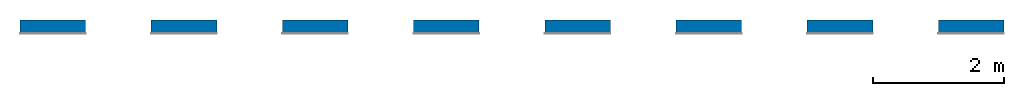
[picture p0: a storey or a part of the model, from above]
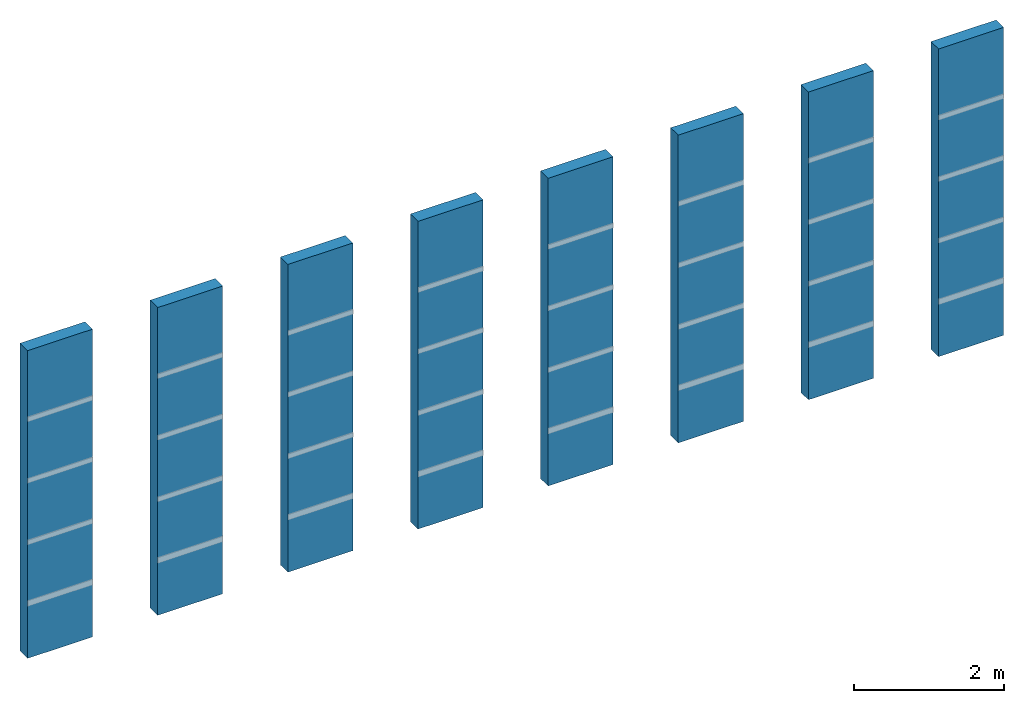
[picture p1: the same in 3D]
Properties of the parts of a building model (IFC2X3), part 2 of 2

# IfcBuildingElementProxy: Wall Sweep:REVIGRÉS-LOCUS-RB-8X90-SILK-ALLOY, Wall Sweep:REVIGRÉS-LOCUS-RB-8X90-SILK-ALLOY:174011
Classification: C3010 (Uniformat)
Pset_ProvisionForVoid - Shape: Undefined; Width: 1000 mm; Depth: 1000 mm
IFC.REVIGRÉS-Dados do fabricante-Wall Sweeps - Type: Wall Sweep: REVIGRÉS-LOCUS-RB-8X90-SILK-ALLOY
IFC.REVIGRÉS-Dados de desempenho-Wall Sweeps - Type: Wall Sweep: REVIGRÉS-LOCUS-RB-8X90-SILK-ALLOY
IFC.REVIGRÉS-Dados de especificação-Wall Sweeps - Type: Wall Sweep: REVIGRÉS-LOCUS-RB-8X90-SILK-ALLOY
IFC.REVIGRÉS-Dados geométricos-Wall Sweeps - Type: Wall Sweep: REVIGRÉS-LOCUS-RB-8X90-SILK-ALLOY
IFC.REVIGRÉS-Dados de sustentabilidade-Wall Sweeps - Type: Wall Sweep: REVIGRÉS-LOCUS-RB-8X90-SILK-ALLOY

# IfcBuildingElementProxy: Wall Sweep:REVIGRÉS-LOCUS-RB-8X90-SILK-BONE, Wall Sweep:REVIGRÉS-LOCUS-RB-8X90-SILK-BONE:174596
In: Level 1
Type - Pset_ManufacturerTypeInformation - Manufacturer: REVIGRÉS
Type - Pset_ProductRequirements - Category: Wall Sweeps
Type - IFC.REVIGRÉS-Dados gerais-Wall Sweeps - Nome: REVIGRÉS-LOCUS-RB-8x90-SILK-BONE; TipoProduto: Prensado a seco: grupo BIa UGL | Grés porcelânico técnico; NumeroDeRegistoDAP: EPD-REV-20240006-CCC1-EN; ReferenciaDAP: -; UrlDOP: -
Type - IFC.REVIGRÉS-Dados do fabricante-Wall Sweeps - FabricanteURL: https://www.revigres.pt/; ReferenciaModelo: Locus; Acabamento: SILK; IdentificadorDoOperadorEconomico: 501840856; UrlFabricanteArtigo: https://www.revigres.pt/colecoes/locus; PaisOrigem: Portugal
Type - IFC.REVIGRÉS-Dados de desempenho-Wall Sweeps - Rectilinearidade: ± 0.2% máx.± 0.8 mm; Ortogonalidade: ± 0.2% máx.± 1.5 mm; PlanaridadeDaSuperficie: ± 0.3% máx. ± 1.8 mm; AbsorcaoDeAgua: < 0.05%; ModuloDeRuptura: > 45 N/mm²; ResistenciaAFlexao: > 2000 N; ResistenciaAAbrasaoProfunda: < 120 mm³; DilatacaoTermicaLinear: ≤ 8,0x10-6 °C-1; ResistenciaAoChoqueTermico: Resiste; DurabilidadeInterior: Cumpre; DurabilidadeResistenciaAoGeloDegelo: Resiste; ResistenciaAoEscorregamentoDIN51097: A; ResistenciaAoEscorregamentoENV51097: A; ResistenciaAoDeslizamentoENV12633: Class 1; ResistenciaAoEscorregamentoBS7976: -; ResistenciaAoEscorregamentoANSIA1371: ≥0,42; ResistenciaAoDeslizamentoBS7976: -; ResistenciaAsManchas: Class 5; LibertacaoDeCadmio: 0; LibertacaoDeChumbo: 0
Type - IFC.REVIGRÉS-Dados de especificação-Wall Sweeps - EPavimento: Sim; ERevestimento: Sim; EExterno: Sim
Type - IFC.REVIGRÉS-Dados geométricos-Wall Sweeps - AlturaNominal: 10.5 mm; ComprimentoNominal: 8 mm; LarguraNominal: 88.9 mm
Type - IFC.REVIGRÉS-Dados de sustentabilidade-Wall Sweeps - ItemEParcialmenteReciclado: 0; PotencialPrivacaoDeAguaConsumoDeAguaPonderado: 4.5; EnergiaTermicaExportada: 0; ItemENovo: Sim; ItemEReciclado: Não; VidaÚtilEsperada: 50; SubstanciasPerigosas: Não; PotencialDeEsgotamentoAbioticoDosRecursosFosseis: 203; PotencialDeEsgotamentoAbioticoDosRecursosNaoFosseisMineraisEMetais: 0.000701; PotencialDeAquecimentoGlobalBiogenico: -0.48; CombustiveisFosseisComPotencialDeAquecimentoGlobal: 13.9; PotencialDeAquecimentoGlobalUsoDoSoloEMudancaDeUsoDoSolo: 0.0246; PotencialDeEutrofizacaoFraccaoDeNutrientesQueAtingemOCompartimentoFinalDeAguaDoce: 0.000189; PotencialDeEutrofizacaoFraccaoDeNutrientesQueAtingemOCompartimentoFinalMarinho: 0.0122; EnergiaRecuperada: 0.00739; ConsumoDeAguaDoce: 0.113; UtilizacaoLiquidaDeAguaDoce: 0.113; ResiduosPerigososEliminados: 0.00221; ResiduosNaoPerigososEliminados: 1.83; MassaTotalDeResiduosRadioactivosEliminados: 0.000394; EnergiaElectricaExportada: 1.55; MateriaisParaRecuperacaoDeEnergia: 0.00739; MateriaisParaReciclagem: 0.0253; UnidadeEPD: 1 m²
Classification: C3010 (Uniformat)
Pset_ProvisionForVoid - Shape: Undefined; Width: 1000 mm; Depth: 1000 mm
IFC.REVIGRÉS-Dados do fabricante-Wall Sweeps - Type: Wall Sweep: REVIGRÉS-LOCUS-RB-8X90-SILK-BONE
IFC.REVIGRÉS-Dados de desempenho-Wall Sweeps - Type: Wall Sweep: REVIGRÉS-LOCUS-RB-8X90-SILK-BONE
IFC.REVIGRÉS-Dados de especificação-Wall Sweeps - Type: Wall Sweep: REVIGRÉS-LOCUS-RB-8X90-SILK-BONE
IFC.REVIGRÉS-Dados geométricos-Wall Sweeps - Type: Wall Sweep: REVIGRÉS-LOCUS-RB-8X90-SILK-BONE
IFC.REVIGRÉS-Dados de sustentabilidade-Wall Sweeps - Type: Wall Sweep: REVIGRÉS-LOCUS-RB-8X90-SILK-BONE

# IfcBuildingElementProxy: Wall Sweep:REVIGRÉS-LOCUS-RB-8X90-SILK-GRIS, Wall Sweep:REVIGRÉS-LOCUS-RB-8X90-SILK-GRIS:174838
In: Level 1
Type - Pset_ManufacturerTypeInformation - Manufacturer: REVIGRÉS
Type - Pset_ProductRequirements - Category: Wall Sweeps
Type - IFC.REVIGRÉS-Dados gerais-Wall Sweeps - Nome: REVIGRÉS-LOCUS-RB-8x90-SILK-GRIS; TipoProduto: Prensado a seco: grupo BIa UGL | Grés porcelânico técnico; NumeroDeRegistoDAP: EPD-REV-20240006-CCC1-EN; ReferenciaDAP: -; UrlDOP: -
Type - IFC.REVIGRÉS-Dados do fabricante-Wall Sweeps - FabricanteURL: https://www.revigres.pt/; ReferenciaModelo: Locus; Acabamento: SILK; IdentificadorDoOperadorEconomico: 501840856; UrlFabricanteArtigo: https://www.revigres.pt/colecoes/locus; PaisOrigem: Portugal
Type - IFC.REVIGRÉS-Dados de desempenho-Wall Sweeps - Rectilinearidade: ± 0.2% máx.± 0.8 mm; Ortogonalidade: ± 0.2% máx.± 1.5 mm; PlanaridadeDaSuperficie: ± 0.3% máx. ± 1.8 mm; AbsorcaoDeAgua: < 0.05%; ModuloDeRuptura: > 45 N/mm²; ResistenciaAFlexao: > 2000 N; ResistenciaAAbrasaoProfunda: < 120 mm³; DilatacaoTermicaLinear: ≤ 8,0x10-6 °C-1; ResistenciaAoChoqueTermico: Resiste; DurabilidadeInterior: Cumpre; DurabilidadeResistenciaAoGeloDegelo: Resiste; ResistenciaAoEscorregamentoDIN51097: A; ResistenciaAoEscorregamentoENV51097: A; ResistenciaAoDeslizamentoENV12633: Class 1; ResistenciaAoEscorregamentoBS7976: -; ResistenciaAoEscorregamentoANSIA1371: ≥0,42; ResistenciaAoDeslizamentoBS7976: -; ResistenciaAsManchas: Class 5; LibertacaoDeCadmio: 0; LibertacaoDeChumbo: 0
Type - IFC.REVIGRÉS-Dados de especificação-Wall Sweeps - EPavimento: Sim; ERevestimento: Sim; EExterno: Sim
Type - IFC.REVIGRÉS-Dados geométricos-Wall Sweeps - AlturaNominal: 10.5 mm; ComprimentoNominal: 8 mm; LarguraNominal: 88.9 mm
Type - IFC.REVIGRÉS-Dados de sustentabilidade-Wall Sweeps - PotencialPrivacaoDeAguaConsumoDeAguaPonderado: 4.5; EnergiaTermicaExportada: 0; ItemENovo: Sim; ItemEParcialmenteReciclado: 0.23; ItemEReciclado: Sim; VidaÚtilEsperada: 50; SubstanciasPerigosas: Não; PotencialDeEsgotamentoAbioticoDosRecursosFosseis: 203; PotencialDeEsgotamentoAbioticoDosRecursosNaoFosseisMineraisEMetais: 0.000701; PotencialDeAquecimentoGlobalBiogenico: -0.48; CombustiveisFosseisComPotencialDeAquecimentoGlobal: 13.9; PotencialDeAquecimentoGlobalUsoDoSoloEMudancaDeUsoDoSolo: 0.0246; PotencialDeEutrofizacaoFraccaoDeNutrientesQueAtingemOCompartimentoFinalDeAguaDoce: 0.000189; PotencialDeEutrofizacaoFraccaoDeNutrientesQueAtingemOCompartimentoFinalMarinho: 0.0122; EnergiaRecuperada: 0.00739; ConsumoDeAguaDoce: 0.113; UtilizacaoLiquidaDeAguaDoce: 0.113; ResiduosPerigososEliminados: 0.00221; ResiduosNaoPerigososEliminados: 1.83; MassaTotalDeResiduosRadioactivosEliminados: 0.000394; EnergiaElectricaExportada: 1.55; MateriaisParaRecuperacaoDeEnergia: 0.00739; MateriaisParaReciclagem: 0.0253; UnidadeEPD: 1 m²
Classification: C3010 (Uniformat)
Pset_ProvisionForVoid - Shape: Undefined; Width: 1000 mm; Depth: 1000 mm
IFC.REVIGRÉS-Dados do fabricante-Wall Sweeps - Type: Wall Sweep: REVIGRÉS-LOCUS-RB-8X90-SILK-GRIS
IFC.REVIGRÉS-Dados de desempenho-Wall Sweeps - Type: Wall Sweep: REVIGRÉS-LOCUS-RB-8X90-SILK-GRIS
IFC.REVIGRÉS-Dados de especificação-Wall Sweeps - Type: Wall Sweep: REVIGRÉS-LOCUS-RB-8X90-SILK-GRIS
IFC.REVIGRÉS-Dados geométricos-Wall Sweeps - Type: Wall Sweep: REVIGRÉS-LOCUS-RB-8X90-SILK-GRIS
IFC.REVIGRÉS-Dados de sustentabilidade-Wall Sweeps - Type: Wall Sweep: REVIGRÉS-LOCUS-RB-8X90-SILK-GRIS

# IfcBuildingElementProxy: Wall Sweep:REVIGRÉS-LOCUS-RB-8X90-SILK-SMOG, Wall Sweep:REVIGRÉS-LOCUS-RB-8X90-SILK-SMOG:174862
In: Level 1
Type - Pset_ManufacturerTypeInformation - Manufacturer: REVIGRÉS
Type - Pset_ProductRequirements - Category: Wall Sweeps
Type - IFC.REVIGRÉS-Dados gerais-Wall Sweeps - Nome: REVIGRÉS-LOCUS-RB-8x90-SILK-SMOG; TipoProduto: Prensado a seco: grupo BIa UGL | Grés porcelânico técnico; NumeroDeRegistoDAP: EPD-REV-20240006-CCC1-EN; ReferenciaDAP: -; UrlDOP: -
Type - IFC.REVIGRÉS-Dados do fabricante-Wall Sweeps - FabricanteURL: https://www.revigres.pt/; ReferenciaModelo: Locus; Acabamento: SILK; IdentificadorDoOperadorEconomico: 501840856; UrlFabricanteArtigo: https://www.revigres.pt/colecoes/locus; PaisOrigem: Portugal
Type - IFC.REVIGRÉS-Dados de desempenho-Wall Sweeps - Rectilinearidade: ± 0.2% máx.± 0.8 mm; Ortogonalidade: ± 0.2% máx.± 1.5 mm; PlanaridadeDaSuperficie: ± 0.3% máx. ± 1.8 mm; AbsorcaoDeAgua: < 0.05%; ModuloDeRuptura: > 45 N/mm²; ResistenciaAFlexao: > 2000 N; ResistenciaAAbrasaoProfunda: < 120 mm³; DilatacaoTermicaLinear: ≤ 8,0x10-6 °C-1; ResistenciaAoChoqueTermico: Resiste; DurabilidadeInterior: Cumpre; DurabilidadeResistenciaAoGeloDegelo: Resiste; ResistenciaAoEscorregamentoDIN51097: A; ResistenciaAoEscorregamentoENV51097: A; ResistenciaAoDeslizamentoENV12633: Class 1; ResistenciaAoEscorregamentoBS7976: -; ResistenciaAoEscorregamentoANSIA1371: ≥0,42; ResistenciaAoDeslizamentoBS7976: -; ResistenciaAsManchas: Class 5; LibertacaoDeCadmio: 0; LibertacaoDeChumbo: 0
Type - IFC.REVIGRÉS-Dados de especificação-Wall Sweeps - EPavimento: Sim; ERevestimento: Sim; EExterno: Sim
Type - IFC.REVIGRÉS-Dados geométricos-Wall Sweeps - AlturaNominal: 10.5 mm; ComprimentoNominal: 8 mm; LarguraNominal: 88.9 mm
Type - IFC.REVIGRÉS-Dados de sustentabilidade-Wall Sweeps - PotencialPrivacaoDeAguaConsumoDeAguaPonderado: 4.5; EnergiaTermicaExportada: 0; ItemENovo: Sim; ItemEParcialmenteReciclado: 0.29; ItemEReciclado: Sim; VidaÚtilEsperada: 50; SubstanciasPerigosas: Não; PotencialDeEsgotamentoAbioticoDosRecursosFosseis: 203; PotencialDeEsgotamentoAbioticoDosRecursosNaoFosseisMineraisEMetais: 0.000701; PotencialDeAquecimentoGlobalBiogenico: -0.48; CombustiveisFosseisComPotencialDeAquecimentoGlobal: 13.9; PotencialDeAquecimentoGlobalUsoDoSoloEMudancaDeUsoDoSolo: 0.0246; PotencialDeEutrofizacaoFraccaoDeNutrientesQueAtingemOCompartimentoFinalDeAguaDoce: 0.000189; PotencialDeEutrofizacaoFraccaoDeNutrientesQueAtingemOCompartimentoFinalMarinho: 0.0122; EnergiaRecuperada: 0.00739; ConsumoDeAguaDoce: 0.113; UtilizacaoLiquidaDeAguaDoce: 0.113; ResiduosPerigososEliminados: 0.00221; ResiduosNaoPerigososEliminados: 1.83; MassaTotalDeResiduosRadioactivosEliminados: 0.000394; EnergiaElectricaExportada: 1.55; MateriaisParaRecuperacaoDeEnergia: 0.00739; MateriaisParaReciclagem: 0.0253; UnidadeEPD: 1 m²
Classification: C3010 (Uniformat)
Pset_ProvisionForVoid - Shape: Undefined; Width: 1000 mm; Depth: 1000 mm
IFC.REVIGRÉS-Dados do fabricante-Wall Sweeps - Type: Wall Sweep: REVIGRÉS-LOCUS-RB-8X90-SILK-SMOG
IFC.REVIGRÉS-Dados de desempenho-Wall Sweeps - Type: Wall Sweep: REVIGRÉS-LOCUS-RB-8X90-SILK-SMOG
IFC.REVIGRÉS-Dados de especificação-Wall Sweeps - Type: Wall Sweep: REVIGRÉS-LOCUS-RB-8X90-SILK-SMOG
IFC.REVIGRÉS-Dados geométricos-Wall Sweeps - Type: Wall Sweep: REVIGRÉS-LOCUS-RB-8X90-SILK-SMOG
IFC.REVIGRÉS-Dados de sustentabilidade-Wall Sweeps - Type: Wall Sweep: REVIGRÉS-LOCUS-RB-8X90-SILK-SMOG

# IfcBuildingElementProxy: Wall Sweep:REVIGRÉS-LOCUS-RB-8X90-SOFT GRIP-ALLOY, Wall Sweep:REVIGRÉS-LOCUS-RB-8X90-SOFT GRIP-ALLOY:174173
In: Level 1
Type - Pset_ManufacturerTypeInformation - Manufacturer: REVIGRÉS
Type - Pset_ProductRequirements - Category: Wall Sweeps
Type - IFC.REVIGRÉS-Dados gerais-Wall Sweeps - Nome: REVIGRÉS-LOCUS-RB-8x90-SOFT GRIP -ALLOY; TipoProduto: Prensado a seco: grupo BIa UGL | Grés porcelânico técnico; NumeroDeRegistoDAP: EPD-REV-20240006-CCC1-EN; ReferenciaDAP: -; UrlDOP: -
Type - IFC.REVIGRÉS-Dados do fabricante-Wall Sweeps - FabricanteURL: https://www.revigres.pt/; ReferenciaModelo: Locus; Acabamento: SOFT; IdentificadorDoOperadorEconomico: 501840856; UrlFabricanteArtigo: https://www.revigres.pt/colecoes/locus; PaisOrigem: Portugal
Type - IFC.REVIGRÉS-Dados de desempenho-Wall Sweeps - Rectilinearidade: ± 0.2% máx ± 1.0 mm; Ortogonalidade: ± 0.2% máx.± 1.5 mm; PlanaridadeDaSuperficie: ± 0.3% máx. ± 1.8 mm; AbsorcaoDeAgua: < 0.05%; ModuloDeRuptura: > 45 N/mm²; ResistenciaAFlexao: > 2000 N; ResistenciaAAbrasaoProfunda: < 120 mm³; DilatacaoTermicaLinear: ≤ 8,0x10-6 °C-1; ResistenciaAoChoqueTermico: Resiste; DurabilidadeInterior: Cumpre; DurabilidadeResistenciaAoGeloDegelo: Resiste; ResistenciaAoEscorregamentoDIN51097: A; ResistenciaAoEscorregamentoENV51097: A; ResistenciaAoDeslizamentoENV12633: Class 2; ResistenciaAoEscorregamentoBS7976: > 36; ResistenciaAoEscorregamentoANSIA1371: ≥0,42; ResistenciaAoDeslizamentoBS7976: > 36; ResistenciaAsManchas: Class 5; LibertacaoDeCadmio: 0; LibertacaoDeChumbo: 0
Type - IFC.REVIGRÉS-Dados de especificação-Wall Sweeps - EPavimento: Sim; ERevestimento: Sim; EExterno: Sim
Type - IFC.REVIGRÉS-Dados geométricos-Wall Sweeps - AlturaNominal: 10.5 mm; ComprimentoNominal: 8 mm; LarguraNominal: 88.9 mm
Type - IFC.REVIGRÉS-Dados de sustentabilidade-Wall Sweeps - ItemEParcialmenteReciclado: 0; PotencialPrivacaoDeAguaConsumoDeAguaPonderado: 4.5; EnergiaTermicaExportada: 0; ItemENovo: Sim; ItemEReciclado: Não; VidaÚtilEsperada: 50; SubstanciasPerigosas: Não; PotencialDeEsgotamentoAbioticoDosRecursosFosseis: 203; PotencialDeEsgotamentoAbioticoDosRecursosNaoFosseisMineraisEMetais: 0.000701; PotencialDeAquecimentoGlobalBiogenico: -0.48; CombustiveisFosseisComPotencialDeAquecimentoGlobal: 13.9; PotencialDeAquecimentoGlobalUsoDoSoloEMudancaDeUsoDoSolo: 0.0246; PotencialDeEutrofizacaoFraccaoDeNutrientesQueAtingemOCompartimentoFinalDeAguaDoce: 0.000189; PotencialDeEutrofizacaoFraccaoDeNutrientesQueAtingemOCompartimentoFinalMarinho: 0.0122; EnergiaRecuperada: 0.00739; ConsumoDeAguaDoce: 0.113; UtilizacaoLiquidaDeAguaDoce: 0.113; ResiduosPerigososEliminados: 0.00221; ResiduosNaoPerigososEliminados: 1.83; MassaTotalDeResiduosRadioactivosEliminados: 0.000394; EnergiaElectricaExportada: 1.55; MateriaisParaRecuperacaoDeEnergia: 0.00739; MateriaisParaReciclagem: 0.0253; UnidadeEPD: 1 m²
Classification: C3010 (Uniformat)
Pset_ProvisionForVoid - Shape: Undefined; Width: 1000 mm; Depth: 1000 mm
IFC.REVIGRÉS-Dados do fabricante-Wall Sweeps - Type: Wall Sweep: REVIGRÉS-LOCUS-RB-8X90-SOFT GRIP-ALLOY
IFC.REVIGRÉS-Dados de desempenho-Wall Sweeps - Type: Wall Sweep: REVIGRÉS-LOCUS-RB-8X90-SOFT GRIP-ALLOY
IFC.REVIGRÉS-Dados de especificação-Wall Sweeps - Type: Wall Sweep: REVIGRÉS-LOCUS-RB-8X90-SOFT GRIP-ALLOY
IFC.REVIGRÉS-Dados geométricos-Wall Sweeps - Type: Wall Sweep: REVIGRÉS-LOCUS-RB-8X90-SOFT GRIP-ALLOY
IFC.REVIGRÉS-Dados de sustentabilidade-Wall Sweeps - Type: Wall Sweep: REVIGRÉS-LOCUS-RB-8X90-SOFT GRIP-ALLOY

# IfcBuildingElementProxy: Wall Sweep:REVIGRÉS-LOCUS-RB-8X90-SOFT GRIP-BONE, Wall Sweep:REVIGRÉS-LOCUS-RB-8X90-SOFT GRIP-BONE:174600
In: Level 1
Type - Pset_ManufacturerTypeInformation - Manufacturer: REVIGRÉS
Type - Pset_ProductRequirements - Category: Wall Sweeps
Type - IFC.REVIGRÉS-Dados gerais-Wall Sweeps - Nome: REVIGRÉS-LOCUS-RB-8x90-SOFT GRIP -BONE; TipoProduto: Prensado a seco: grupo BIa UGL | Grés porcelânico técnico; NumeroDeRegistoDAP: EPD-REV-20240006-CCC1-EN; ReferenciaDAP: -; UrlDOP: -
Type - IFC.REVIGRÉS-Dados do fabricante-Wall Sweeps - FabricanteURL: https://www.revigres.pt/; ReferenciaModelo: Locus; Acabamento: SOFT; IdentificadorDoOperadorEconomico: 501840856; UrlFabricanteArtigo: https://www.revigres.pt/colecoes/locus; PaisOrigem: Portugal
Type - IFC.REVIGRÉS-Dados de desempenho-Wall Sweeps - Rectilinearidade: ± 0.2% máx ± 1.0 mm; Ortogonalidade: ± 0.2% máx.± 1.5 mm; PlanaridadeDaSuperficie: ± 0.3% máx. ± 1.8 mm; AbsorcaoDeAgua: < 0.05%; ModuloDeRuptura: > 45 N/mm²; ResistenciaAFlexao: > 2000 N; ResistenciaAAbrasaoProfunda: < 120 mm³; DilatacaoTermicaLinear: ≤ 8,0x10-6 °C-1; ResistenciaAoChoqueTermico: Resiste; DurabilidadeInterior: Cumpre; DurabilidadeResistenciaAoGeloDegelo: Resiste; ResistenciaAoEscorregamentoDIN51097: A; ResistenciaAoEscorregamentoENV51097: A; ResistenciaAoDeslizamentoENV12633: Class 2; ResistenciaAoEscorregamentoBS7976: > 36; ResistenciaAoEscorregamentoANSIA1371: ≥0,42; ResistenciaAoDeslizamentoBS7976: > 36; ResistenciaAsManchas: Class 5; LibertacaoDeCadmio: 0; LibertacaoDeChumbo: 0
Type - IFC.REVIGRÉS-Dados de especificação-Wall Sweeps - EPavimento: Sim; ERevestimento: Sim; EExterno: Sim
Type - IFC.REVIGRÉS-Dados geométricos-Wall Sweeps - AlturaNominal: 10.5 mm; ComprimentoNominal: 8 mm; LarguraNominal: 88.9 mm
Type - IFC.REVIGRÉS-Dados de sustentabilidade-Wall Sweeps - ItemEParcialmenteReciclado: 0; PotencialPrivacaoDeAguaConsumoDeAguaPonderado: 4.5; EnergiaTermicaExportada: 0; ItemENovo: Sim; ItemEReciclado: Não; VidaÚtilEsperada: 50; SubstanciasPerigosas: Não; PotencialDeEsgotamentoAbioticoDosRecursosFosseis: 203; PotencialDeEsgotamentoAbioticoDosRecursosNaoFosseisMineraisEMetais: 0.000701; PotencialDeAquecimentoGlobalBiogenico: -0.48; CombustiveisFosseisComPotencialDeAquecimentoGlobal: 13.9; PotencialDeAquecimentoGlobalUsoDoSoloEMudancaDeUsoDoSolo: 0.0246; PotencialDeEutrofizacaoFraccaoDeNutrientesQueAtingemOCompartimentoFinalDeAguaDoce: 0.000189; PotencialDeEutrofizacaoFraccaoDeNutrientesQueAtingemOCompartimentoFinalMarinho: 0.0122; EnergiaRecuperada: 0.00739; ConsumoDeAguaDoce: 0.113; UtilizacaoLiquidaDeAguaDoce: 0.113; ResiduosPerigososEliminados: 0.00221; ResiduosNaoPerigososEliminados: 1.83; MassaTotalDeResiduosRadioactivosEliminados: 0.000394; EnergiaElectricaExportada: 1.55; MateriaisParaRecuperacaoDeEnergia: 0.00739; MateriaisParaReciclagem: 0.0253; UnidadeEPD: 1 m²
Classification: C3010 (Uniformat)
Pset_ProvisionForVoid - Shape: Undefined; Width: 1000 mm; Depth: 1000 mm
IFC.REVIGRÉS-Dados do fabricante-Wall Sweeps - Type: Wall Sweep: REVIGRÉS-LOCUS-RB-8X90-SOFT GRIP-BONE
IFC.REVIGRÉS-Dados de desempenho-Wall Sweeps - Type: Wall Sweep: REVIGRÉS-LOCUS-RB-8X90-SOFT GRIP-BONE
IFC.REVIGRÉS-Dados de especificação-Wall Sweeps - Type: Wall Sweep: REVIGRÉS-LOCUS-RB-8X90-SOFT GRIP-BONE
IFC.REVIGRÉS-Dados geométricos-Wall Sweeps - Type: Wall Sweep: REVIGRÉS-LOCUS-RB-8X90-SOFT GRIP-BONE
IFC.REVIGRÉS-Dados de sustentabilidade-Wall Sweeps - Type: Wall Sweep: REVIGRÉS-LOCUS-RB-8X90-SOFT GRIP-BONE

# IfcBuildingElementProxy: Wall Sweep:REVIGRÉS-LOCUS-RB-8X90-SOFT GRIP-GRIS, Wall Sweep:REVIGRÉS-LOCUS-RB-8X90-SOFT GRIP-GRIS:174842
In: Level 1
Type - Pset_ManufacturerTypeInformation - Manufacturer: REVIGRÉS
Type - Pset_ProductRequirements - Category: Wall Sweeps
Type - IFC.REVIGRÉS-Dados gerais-Wall Sweeps - Nome: REVIGRÉS-LOCUS-RB-8x90-SOFT GRIP -GRIS; TipoProduto: Prensado a seco: grupo BIa UGL | Grés porcelânico técnico; NumeroDeRegistoDAP: EPD-REV-20240006-CCC1-EN; ReferenciaDAP: -; UrlDOP: -
Type - IFC.REVIGRÉS-Dados do fabricante-Wall Sweeps - FabricanteURL: https://www.revigres.pt/; ReferenciaModelo: Locus; Acabamento: SOFT; IdentificadorDoOperadorEconomico: 501840856; UrlFabricanteArtigo: https://www.revigres.pt/colecoes/locus; PaisOrigem: Portugal
Type - IFC.REVIGRÉS-Dados de desempenho-Wall Sweeps - Rectilinearidade: ± 0.2% máx ± 1.0 mm; Ortogonalidade: ± 0.2% máx.± 1.5 mm; PlanaridadeDaSuperficie: ± 0.3% máx. ± 1.8 mm; AbsorcaoDeAgua: < 0.05%; ModuloDeRuptura: > 45 N/mm²; ResistenciaAFlexao: > 2000 N; ResistenciaAAbrasaoProfunda: < 120 mm³; DilatacaoTermicaLinear: ≤ 8,0x10-6 °C-1; ResistenciaAoChoqueTermico: Resiste; DurabilidadeInterior: Cumpre; DurabilidadeResistenciaAoGeloDegelo: Resiste; ResistenciaAoEscorregamentoDIN51097: A; ResistenciaAoEscorregamentoENV51097: A; ResistenciaAoDeslizamentoENV12633: Class 2; ResistenciaAoEscorregamentoBS7976: > 36; ResistenciaAoEscorregamentoANSIA1371: ≥0,42; ResistenciaAoDeslizamentoBS7976: > 36; ResistenciaAsManchas: Class 5; LibertacaoDeCadmio: 0; LibertacaoDeChumbo: 0
Type - IFC.REVIGRÉS-Dados de especificação-Wall Sweeps - EPavimento: Sim; ERevestimento: Sim; EExterno: Sim
Type - IFC.REVIGRÉS-Dados geométricos-Wall Sweeps - AlturaNominal: 10.5 mm; ComprimentoNominal: 8 mm; LarguraNominal: 88.9 mm
Type - IFC.REVIGRÉS-Dados de sustentabilidade-Wall Sweeps - PotencialPrivacaoDeAguaConsumoDeAguaPonderado: 4.5; EnergiaTermicaExportada: 0; ItemENovo: Sim; ItemEParcialmenteReciclado: 0.23; ItemEReciclado: Sim; VidaÚtilEsperada: 50; SubstanciasPerigosas: Não; PotencialDeEsgotamentoAbioticoDosRecursosFosseis: 203; PotencialDeEsgotamentoAbioticoDosRecursosNaoFosseisMineraisEMetais: 0.000701; PotencialDeAquecimentoGlobalBiogenico: -0.48; CombustiveisFosseisComPotencialDeAquecimentoGlobal: 13.9; PotencialDeAquecimentoGlobalUsoDoSoloEMudancaDeUsoDoSolo: 0.0246; PotencialDeEutrofizacaoFraccaoDeNutrientesQueAtingemOCompartimentoFinalDeAguaDoce: 0.000189; PotencialDeEutrofizacaoFraccaoDeNutrientesQueAtingemOCompartimentoFinalMarinho: 0.0122; EnergiaRecuperada: 0.00739; ConsumoDeAguaDoce: 0.113; UtilizacaoLiquidaDeAguaDoce: 0.113; ResiduosPerigososEliminados: 0.00221; ResiduosNaoPerigososEliminados: 1.83; MassaTotalDeResiduosRadioactivosEliminados: 0.000394; EnergiaElectricaExportada: 1.55; MateriaisParaRecuperacaoDeEnergia: 0.00739; MateriaisParaReciclagem: 0.0253; UnidadeEPD: 1 m²
Classification: C3010 (Uniformat)
Pset_ProvisionForVoid - Shape: Undefined; Width: 1000 mm; Depth: 1000 mm
IFC.REVIGRÉS-Dados do fabricante-Wall Sweeps - Type: Wall Sweep: REVIGRÉS-LOCUS-RB-8X90-SOFT GRIP-GRIS
IFC.REVIGRÉS-Dados de desempenho-Wall Sweeps - Type: Wall Sweep: REVIGRÉS-LOCUS-RB-8X90-SOFT GRIP-GRIS
IFC.REVIGRÉS-Dados de especificação-Wall Sweeps - Type: Wall Sweep: REVIGRÉS-LOCUS-RB-8X90-SOFT GRIP-GRIS
IFC.REVIGRÉS-Dados geométricos-Wall Sweeps - Type: Wall Sweep: REVIGRÉS-LOCUS-RB-8X90-SOFT GRIP-GRIS
IFC.REVIGRÉS-Dados de sustentabilidade-Wall Sweeps - Type: Wall Sweep: REVIGRÉS-LOCUS-RB-8X90-SOFT GRIP-GRIS

# IfcBuildingElementProxy: Wall Sweep:REVIGRÉS-LOCUS-RB-8X90-SOFT GRIP-SMOG, Wall Sweep:REVIGRÉS-LOCUS-RB-8X90-SOFT GRIP-SMOG:174866
In: Level 1
Type - Pset_ManufacturerTypeInformation - Manufacturer: REVIGRÉS
Type - Pset_ProductRequirements - Category: Wall Sweeps
Type - IFC.REVIGRÉS-Dados gerais-Wall Sweeps - Nome: REVIGRÉS-LOCUS-RB-8x90-SOFT GRIP -SMOG; TipoProduto: Prensado a seco: grupo BIa UGL | Grés porcelânico técnico; NumeroDeRegistoDAP: EPD-REV-20240006-CCC1-EN; ReferenciaDAP: -; UrlDOP: -
Type - IFC.REVIGRÉS-Dados do fabricante-Wall Sweeps - FabricanteURL: https://www.revigres.pt/; ReferenciaModelo: Locus; Acabamento: SOFT; IdentificadorDoOperadorEconomico: 501840856; UrlFabricanteArtigo: https://www.revigres.pt/colecoes/locus; PaisOrigem: Portugal
Type - IFC.REVIGRÉS-Dados de desempenho-Wall Sweeps - Rectilinearidade: ± 0.2% máx ± 1.0 mm; Ortogonalidade: ± 0.2% máx.± 1.5 mm; PlanaridadeDaSuperficie: ± 0.3% máx. ± 1.8 mm; AbsorcaoDeAgua: < 0.05%; ModuloDeRuptura: > 45 N/mm²; ResistenciaAFlexao: > 2000 N; ResistenciaAAbrasaoProfunda: < 120 mm³; DilatacaoTermicaLinear: ≤ 8,0x10-6 °C-1; ResistenciaAoChoqueTermico: Resiste; DurabilidadeInterior: Cumpre; DurabilidadeResistenciaAoGeloDegelo: Resiste; ResistenciaAoEscorregamentoDIN51097: A; ResistenciaAoEscorregamentoENV51097: A; ResistenciaAoDeslizamentoENV12633: Class 2; ResistenciaAoEscorregamentoBS7976: > 36; ResistenciaAoEscorregamentoANSIA1371: ≥0,42; ResistenciaAoDeslizamentoBS7976: > 36; ResistenciaAsManchas: Class 5; LibertacaoDeCadmio: 0; LibertacaoDeChumbo: 0
Type - IFC.REVIGRÉS-Dados de especificação-Wall Sweeps - EPavimento: Sim; ERevestimento: Sim; EExterno: Sim
Type - IFC.REVIGRÉS-Dados geométricos-Wall Sweeps - AlturaNominal: 10.5 mm; ComprimentoNominal: 8 mm; LarguraNominal: 88.9 mm
Type - IFC.REVIGRÉS-Dados de sustentabilidade-Wall Sweeps - PotencialPrivacaoDeAguaConsumoDeAguaPonderado: 4.5; EnergiaTermicaExportada: 0; ItemENovo: Sim; ItemEParcialmenteReciclado: 0.29; ItemEReciclado: Sim; VidaÚtilEsperada: 50; SubstanciasPerigosas: Não; PotencialDeEsgotamentoAbioticoDosRecursosFosseis: 203; PotencialDeEsgotamentoAbioticoDosRecursosNaoFosseisMineraisEMetais: 0.000701; PotencialDeAquecimentoGlobalBiogenico: -0.48; CombustiveisFosseisComPotencialDeAquecimentoGlobal: 13.9; PotencialDeAquecimentoGlobalUsoDoSoloEMudancaDeUsoDoSolo: 0.0246; PotencialDeEutrofizacaoFraccaoDeNutrientesQueAtingemOCompartimentoFinalDeAguaDoce: 0.000189; PotencialDeEutrofizacaoFraccaoDeNutrientesQueAtingemOCompartimentoFinalMarinho: 0.0122; EnergiaRecuperada: 0.00739; ConsumoDeAguaDoce: 0.113; UtilizacaoLiquidaDeAguaDoce: 0.113; ResiduosPerigososEliminados: 0.00221; ResiduosNaoPerigososEliminados: 1.83; MassaTotalDeResiduosRadioactivosEliminados: 0.000394; EnergiaElectricaExportada: 1.55; MateriaisParaRecuperacaoDeEnergia: 0.00739; MateriaisParaReciclagem: 0.0253; UnidadeEPD: 1 m²
Classification: C3010 (Uniformat)
Pset_ProvisionForVoid - Shape: Undefined; Width: 1000 mm; Depth: 1000 mm
IFC.REVIGRÉS-Dados do fabricante-Wall Sweeps - Type: Wall Sweep: REVIGRÉS-LOCUS-RB-8X90-SOFT GRIP-SMOG
IFC.REVIGRÉS-Dados de desempenho-Wall Sweeps - Type: Wall Sweep: REVIGRÉS-LOCUS-RB-8X90-SOFT GRIP-SMOG
IFC.REVIGRÉS-Dados de especificação-Wall Sweeps - Type: Wall Sweep: REVIGRÉS-LOCUS-RB-8X90-SOFT GRIP-SMOG
IFC.REVIGRÉS-Dados geométricos-Wall Sweeps - Type: Wall Sweep: REVIGRÉS-LOCUS-RB-8X90-SOFT GRIP-SMOG
IFC.REVIGRÉS-Dados de sustentabilidade-Wall Sweeps - Type: Wall Sweep: REVIGRÉS-LOCUS-RB-8X90-SOFT GRIP-SMOG

# IfcBuildingElementProxy: Wall Sweep:REVIGRÉS-LOCUS-RB-9,5X30-SILK-ALLOY, Wall Sweep:REVIGRÉS-LOCUS-RB-9,5X30-SILK-ALLOY:174039
In: Level 1
Type - Pset_ManufacturerTypeInformation - Manufacturer: REVIGRÉS
Type - Pset_ProductRequirements - Category: Wall Sweeps
Type - IFC.REVIGRÉS-Dados gerais-Wall Sweeps - Nome: REVIGRÉS-LOCUS-RB-9.5x30-SILK-ALLOY; TipoProduto: Prensado a seco: grupo BIa UGL | Grés porcelânico técnico; NumeroDeRegistoDAP: EPD-REV-20240006-CCC1-EN; ReferenciaDAP: -; UrlDOP: -
Type - IFC.REVIGRÉS-Dados do fabricante-Wall Sweeps - FabricanteURL: https://www.revigres.pt/; ReferenciaModelo: Locus; Acabamento: SILK; IdentificadorDoOperadorEconomico: 501840856; UrlFabricanteArtigo: https://www.revigres.pt/colecoes/locus; PaisOrigem: Portugal
Type - IFC.REVIGRÉS-Dados de desempenho-Wall Sweeps - Rectilinearidade: ± 0.2% máx.± 0.8 mm; Ortogonalidade: ± 0.2% máx.± 1.5 mm; PlanaridadeDaSuperficie: ± 0.3% máx. ± 1.8 mm; AbsorcaoDeAgua: < 0.05%; ModuloDeRuptura: > 45 N/mm²; ResistenciaAFlexao: > 2000 N; ResistenciaAAbrasaoProfunda: < 120 mm³; DilatacaoTermicaLinear: ≤ 8,0x10-6 °C-1; ResistenciaAoChoqueTermico: Resiste; DurabilidadeInterior: Cumpre; DurabilidadeResistenciaAoGeloDegelo: Resiste; ResistenciaAoEscorregamentoDIN51097: A; ResistenciaAoEscorregamentoENV51097: A; ResistenciaAoDeslizamentoENV12633: Class 1; ResistenciaAoEscorregamentoBS7976: -; ResistenciaAoEscorregamentoANSIA1371: ≥0,42; ResistenciaAoDeslizamentoBS7976: -; ResistenciaAsManchas: Class 5; LibertacaoDeCadmio: 0; LibertacaoDeChumbo: 0
Type - IFC.REVIGRÉS-Dados de especificação-Wall Sweeps - EPavimento: Sim; ERevestimento: Sim; EExterno: Sim
Type - IFC.REVIGRÉS-Dados geométricos-Wall Sweeps - AlturaNominal: 8.5 mm; ComprimentoNominal: 9.5 mm; LarguraNominal: 29.5 mm
Type - IFC.REVIGRÉS-Dados de sustentabilidade-Wall Sweeps - ItemEParcialmenteReciclado: 0; PotencialPrivacaoDeAguaConsumoDeAguaPonderado: 4.5; EnergiaTermicaExportada: 0; ItemENovo: Sim; ItemEReciclado: Não; VidaÚtilEsperada: 50; SubstanciasPerigosas: Não; PotencialDeEsgotamentoAbioticoDosRecursosFosseis: 203; PotencialDeEsgotamentoAbioticoDosRecursosNaoFosseisMineraisEMetais: 0.000701; PotencialDeAquecimentoGlobalBiogenico: -0.48; CombustiveisFosseisComPotencialDeAquecimentoGlobal: 13.9; PotencialDeAquecimentoGlobalUsoDoSoloEMudancaDeUsoDoSolo: 0.0246; PotencialDeEutrofizacaoFraccaoDeNutrientesQueAtingemOCompartimentoFinalDeAguaDoce: 0.000189; PotencialDeEutrofizacaoFraccaoDeNutrientesQueAtingemOCompartimentoFinalMarinho: 0.0122; EnergiaRecuperada: 0.00739; ConsumoDeAguaDoce: 0.113; UtilizacaoLiquidaDeAguaDoce: 0.113; ResiduosPerigososEliminados: 0.00221; ResiduosNaoPerigososEliminados: 1.83; MassaTotalDeResiduosRadioactivosEliminados: 0.000394; EnergiaElectricaExportada: 1.55; MateriaisParaRecuperacaoDeEnergia: 0.00739; MateriaisParaReciclagem: 0.0253; UnidadeEPD: 1 m²
Classification: C3010 (Uniformat)
Pset_ProvisionForVoid - Shape: Undefined; Width: 1000 mm; Depth: 1000 mm
IFC.REVIGRÉS-Dados do fabricante-Wall Sweeps - Type: Wall Sweep: REVIGRÉS-LOCUS-RB-9,5X30-SILK-ALLOY
IFC.REVIGRÉS-Dados de desempenho-Wall Sweeps - Type: Wall Sweep: REVIGRÉS-LOCUS-RB-9,5X30-SILK-ALLOY
IFC.REVIGRÉS-Dados de especificação-Wall Sweeps - Type: Wall Sweep: REVIGRÉS-LOCUS-RB-9,5X30-SILK-ALLOY
IFC.REVIGRÉS-Dados geométricos-Wall Sweeps - Type: Wall Sweep: REVIGRÉS-LOCUS-RB-9,5X30-SILK-ALLOY
IFC.REVIGRÉS-Dados de sustentabilidade-Wall Sweeps - Type: Wall Sweep: REVIGRÉS-LOCUS-RB-9,5X30-SILK-ALLOY

# IfcBuildingElementProxy: Wall Sweep:REVIGRÉS-LOCUS-RB-9,5X30-SILK-BONE, Wall Sweep:REVIGRÉS-LOCUS-RB-9,5X30-SILK-BONE:174598
In: Level 1
Type - Pset_ManufacturerTypeInformation - Manufacturer: REVIGRÉS
Type - Pset_ProductRequirements - Category: Wall Sweeps
Type - IFC.REVIGRÉS-Dados gerais-Wall Sweeps - Nome: REVIGRÉS-LOCUS-RB-9.5x30-SILK-BONE; TipoProduto: Prensado a seco: grupo BIa UGL | Grés porcelânico técnico; NumeroDeRegistoDAP: EPD-REV-20240006-CCC1-EN; ReferenciaDAP: -; UrlDOP: -
Type - IFC.REVIGRÉS-Dados do fabricante-Wall Sweeps - FabricanteURL: https://www.revigres.pt/; ReferenciaModelo: Locus; Acabamento: SILK; IdentificadorDoOperadorEconomico: 501840856; UrlFabricanteArtigo: https://www.revigres.pt/colecoes/locus; PaisOrigem: Portugal
Type - IFC.REVIGRÉS-Dados de desempenho-Wall Sweeps - Rectilinearidade: ± 0.2% máx.± 0.8 mm; Ortogonalidade: ± 0.2% máx.± 1.5 mm; PlanaridadeDaSuperficie: ± 0.3% máx. ± 1.8 mm; AbsorcaoDeAgua: < 0.05%; ModuloDeRuptura: > 45 N/mm²; ResistenciaAFlexao: > 2000 N; ResistenciaAAbrasaoProfunda: < 120 mm³; DilatacaoTermicaLinear: ≤ 8,0x10-6 °C-1; ResistenciaAoChoqueTermico: Resiste; DurabilidadeInterior: Cumpre; DurabilidadeResistenciaAoGeloDegelo: Resiste; ResistenciaAoEscorregamentoDIN51097: A; ResistenciaAoEscorregamentoENV51097: A; ResistenciaAoDeslizamentoENV12633: Class 1; ResistenciaAoEscorregamentoBS7976: -; ResistenciaAoEscorregamentoANSIA1371: ≥0,42; ResistenciaAoDeslizamentoBS7976: -; ResistenciaAsManchas: Class 5; LibertacaoDeCadmio: 0; LibertacaoDeChumbo: 0
Type - IFC.REVIGRÉS-Dados de especificação-Wall Sweeps - EPavimento: Sim; ERevestimento: Sim; EExterno: Sim
Type - IFC.REVIGRÉS-Dados geométricos-Wall Sweeps - AlturaNominal: 8.5 mm; ComprimentoNominal: 9.5 mm; LarguraNominal: 29.5 mm
Type - IFC.REVIGRÉS-Dados de sustentabilidade-Wall Sweeps - ItemEParcialmenteReciclado: 0; PotencialPrivacaoDeAguaConsumoDeAguaPonderado: 4.5; EnergiaTermicaExportada: 0; ItemENovo: Sim; ItemEReciclado: Não; VidaÚtilEsperada: 50; SubstanciasPerigosas: Não; PotencialDeEsgotamentoAbioticoDosRecursosFosseis: 203; PotencialDeEsgotamentoAbioticoDosRecursosNaoFosseisMineraisEMetais: 0.000701; PotencialDeAquecimentoGlobalBiogenico: -0.48; CombustiveisFosseisComPotencialDeAquecimentoGlobal: 13.9; PotencialDeAquecimentoGlobalUsoDoSoloEMudancaDeUsoDoSolo: 0.0246; PotencialDeEutrofizacaoFraccaoDeNutrientesQueAtingemOCompartimentoFinalDeAguaDoce: 0.000189; PotencialDeEutrofizacaoFraccaoDeNutrientesQueAtingemOCompartimentoFinalMarinho: 0.0122; EnergiaRecuperada: 0.00739; ConsumoDeAguaDoce: 0.113; UtilizacaoLiquidaDeAguaDoce: 0.113; ResiduosPerigososEliminados: 0.00221; ResiduosNaoPerigososEliminados: 1.83; MassaTotalDeResiduosRadioactivosEliminados: 0.000394; EnergiaElectricaExportada: 1.55; MateriaisParaRecuperacaoDeEnergia: 0.00739; MateriaisParaReciclagem: 0.0253; UnidadeEPD: 1 m²
Classification: C3010 (Uniformat)
Pset_ProvisionForVoid - Shape: Undefined; Width: 1000 mm; Depth: 1000 mm
IFC.REVIGRÉS-Dados do fabricante-Wall Sweeps - Type: Wall Sweep: REVIGRÉS-LOCUS-RB-9,5X30-SILK-BONE
IFC.REVIGRÉS-Dados de desempenho-Wall Sweeps - Type: Wall Sweep: REVIGRÉS-LOCUS-RB-9,5X30-SILK-BONE
IFC.REVIGRÉS-Dados de especificação-Wall Sweeps - Type: Wall Sweep: REVIGRÉS-LOCUS-RB-9,5X30-SILK-BONE
IFC.REVIGRÉS-Dados geométricos-Wall Sweeps - Type: Wall Sweep: REVIGRÉS-LOCUS-RB-9,5X30-SILK-BONE
IFC.REVIGRÉS-Dados de sustentabilidade-Wall Sweeps - Type: Wall Sweep: REVIGRÉS-LOCUS-RB-9,5X30-SILK-BONE

# IfcBuildingElementProxy: Wall Sweep:REVIGRÉS-LOCUS-RB-9,5X30-SILK-GRIS, Wall Sweep:REVIGRÉS-LOCUS-RB-9,5X30-SILK-GRIS:174840
In: Level 1
Type - Pset_ManufacturerTypeInformation - Manufacturer: REVIGRÉS
Type - Pset_ProductRequirements - Category: Wall Sweeps
Type - IFC.REVIGRÉS-Dados gerais-Wall Sweeps - Nome: REVIGRÉS-LOCUS-RB-9.5x30-SILK-GRIS; TipoProduto: Prensado a seco: grupo BIa UGL | Grés porcelânico técnico; NumeroDeRegistoDAP: EPD-REV-20240006-CCC1-EN; ReferenciaDAP: -; UrlDOP: -
Type - IFC.REVIGRÉS-Dados do fabricante-Wall Sweeps - FabricanteURL: https://www.revigres.pt/; ReferenciaModelo: Locus; Acabamento: SILK; IdentificadorDoOperadorEconomico: 501840856; UrlFabricanteArtigo: https://www.revigres.pt/colecoes/locus; PaisOrigem: Portugal
Type - IFC.REVIGRÉS-Dados de desempenho-Wall Sweeps - Rectilinearidade: ± 0.2% máx.± 0.8 mm; Ortogonalidade: ± 0.2% máx.± 1.5 mm; PlanaridadeDaSuperficie: ± 0.3% máx. ± 1.8 mm; AbsorcaoDeAgua: < 0.05%; ModuloDeRuptura: > 45 N/mm²; ResistenciaAFlexao: > 2000 N; ResistenciaAAbrasaoProfunda: < 120 mm³; DilatacaoTermicaLinear: ≤ 8,0x10-6 °C-1; ResistenciaAoChoqueTermico: Resiste; DurabilidadeInterior: Cumpre; DurabilidadeResistenciaAoGeloDegelo: Resiste; ResistenciaAoEscorregamentoDIN51097: A; ResistenciaAoEscorregamentoENV51097: A; ResistenciaAoDeslizamentoENV12633: Class 1; ResistenciaAoEscorregamentoBS7976: -; ResistenciaAoEscorregamentoANSIA1371: ≥0,42; ResistenciaAoDeslizamentoBS7976: -; ResistenciaAsManchas: Class 5; LibertacaoDeCadmio: 0; LibertacaoDeChumbo: 0
Type - IFC.REVIGRÉS-Dados de especificação-Wall Sweeps - EPavimento: Sim; ERevestimento: Sim; EExterno: Sim
Type - IFC.REVIGRÉS-Dados geométricos-Wall Sweeps - AlturaNominal: 8.5 mm; ComprimentoNominal: 9.5 mm; LarguraNominal: 29.5 mm
Type - IFC.REVIGRÉS-Dados de sustentabilidade-Wall Sweeps - PotencialPrivacaoDeAguaConsumoDeAguaPonderado: 4.5; EnergiaTermicaExportada: 0; ItemENovo: Sim; ItemEParcialmenteReciclado: 0.23; ItemEReciclado: Sim; VidaÚtilEsperada: 50; SubstanciasPerigosas: Não; PotencialDeEsgotamentoAbioticoDosRecursosFosseis: 203; PotencialDeEsgotamentoAbioticoDosRecursosNaoFosseisMineraisEMetais: 0.000701; PotencialDeAquecimentoGlobalBiogenico: -0.48; CombustiveisFosseisComPotencialDeAquecimentoGlobal: 13.9; PotencialDeAquecimentoGlobalUsoDoSoloEMudancaDeUsoDoSolo: 0.0246; PotencialDeEutrofizacaoFraccaoDeNutrientesQueAtingemOCompartimentoFinalDeAguaDoce: 0.000189; PotencialDeEutrofizacaoFraccaoDeNutrientesQueAtingemOCompartimentoFinalMarinho: 0.0122; EnergiaRecuperada: 0.00739; ConsumoDeAguaDoce: 0.113; UtilizacaoLiquidaDeAguaDoce: 0.113; ResiduosPerigososEliminados: 0.00221; ResiduosNaoPerigososEliminados: 1.83; MassaTotalDeResiduosRadioactivosEliminados: 0.000394; EnergiaElectricaExportada: 1.55; MateriaisParaRecuperacaoDeEnergia: 0.00739; MateriaisParaReciclagem: 0.0253; UnidadeEPD: 1 m²
Classification: C3010 (Uniformat)
Pset_ProvisionForVoid - Shape: Undefined; Width: 1000 mm; Depth: 1000 mm
IFC.REVIGRÉS-Dados do fabricante-Wall Sweeps - Type: Wall Sweep: REVIGRÉS-LOCUS-RB-9,5X30-SILK-GRIS
IFC.REVIGRÉS-Dados de desempenho-Wall Sweeps - Type: Wall Sweep: REVIGRÉS-LOCUS-RB-9,5X30-SILK-GRIS
IFC.REVIGRÉS-Dados de especificação-Wall Sweeps - Type: Wall Sweep: REVIGRÉS-LOCUS-RB-9,5X30-SILK-GRIS
IFC.REVIGRÉS-Dados geométricos-Wall Sweeps - Type: Wall Sweep: REVIGRÉS-LOCUS-RB-9,5X30-SILK-GRIS
IFC.REVIGRÉS-Dados de sustentabilidade-Wall Sweeps - Type: Wall Sweep: REVIGRÉS-LOCUS-RB-9,5X30-SILK-GRIS

# IfcBuildingElementProxy: Wall Sweep:REVIGRÉS-LOCUS-RB-9,5X30-SILK-SMOG, Wall Sweep:REVIGRÉS-LOCUS-RB-9,5X30-SILK-SMOG:174864
In: Level 1
Type - Pset_ManufacturerTypeInformation - Manufacturer: REVIGRÉS
Type - Pset_ProductRequirements - Category: Wall Sweeps
Type - IFC.REVIGRÉS-Dados gerais-Wall Sweeps - Nome: REVIGRÉS-LOCUS-RB-9.5x30-SILK-SMOG; TipoProduto: Prensado a seco: grupo BIa UGL | Grés porcelânico técnico; NumeroDeRegistoDAP: EPD-REV-20240006-CCC1-EN; ReferenciaDAP: -; UrlDOP: -
Type - IFC.REVIGRÉS-Dados do fabricante-Wall Sweeps - FabricanteURL: https://www.revigres.pt/; ReferenciaModelo: Locus; Acabamento: SILK; IdentificadorDoOperadorEconomico: 501840856; UrlFabricanteArtigo: https://www.revigres.pt/colecoes/locus; PaisOrigem: Portugal
Type - IFC.REVIGRÉS-Dados de desempenho-Wall Sweeps - Rectilinearidade: ± 0.2% máx.± 0.8 mm; Ortogonalidade: ± 0.2% máx.± 1.5 mm; PlanaridadeDaSuperficie: ± 0.3% máx. ± 1.8 mm; AbsorcaoDeAgua: < 0.05%; ModuloDeRuptura: > 45 N/mm²; ResistenciaAFlexao: > 2000 N; ResistenciaAAbrasaoProfunda: < 120 mm³; DilatacaoTermicaLinear: ≤ 8,0x10-6 °C-1; ResistenciaAoChoqueTermico: Resiste; DurabilidadeInterior: Cumpre; DurabilidadeResistenciaAoGeloDegelo: Resiste; ResistenciaAoEscorregamentoDIN51097: A; ResistenciaAoEscorregamentoENV51097: A; ResistenciaAoDeslizamentoENV12633: Class 1; ResistenciaAoEscorregamentoBS7976: -; ResistenciaAoEscorregamentoANSIA1371: ≥0,42; ResistenciaAoDeslizamentoBS7976: -; ResistenciaAsManchas: Class 5; LibertacaoDeCadmio: 0; LibertacaoDeChumbo: 0
Type - IFC.REVIGRÉS-Dados de especificação-Wall Sweeps - EPavimento: Sim; ERevestimento: Sim; EExterno: Sim
Type - IFC.REVIGRÉS-Dados geométricos-Wall Sweeps - AlturaNominal: 8.5 mm; ComprimentoNominal: 9.5 mm; LarguraNominal: 29.5 mm
Type - IFC.REVIGRÉS-Dados de sustentabilidade-Wall Sweeps - PotencialPrivacaoDeAguaConsumoDeAguaPonderado: 4.5; EnergiaTermicaExportada: 0; ItemENovo: Sim; ItemEParcialmenteReciclado: 0.29; ItemEReciclado: Sim; VidaÚtilEsperada: 50; SubstanciasPerigosas: Não; PotencialDeEsgotamentoAbioticoDosRecursosFosseis: 203; PotencialDeEsgotamentoAbioticoDosRecursosNaoFosseisMineraisEMetais: 0.000701; PotencialDeAquecimentoGlobalBiogenico: -0.48; CombustiveisFosseisComPotencialDeAquecimentoGlobal: 13.9; PotencialDeAquecimentoGlobalUsoDoSoloEMudancaDeUsoDoSolo: 0.0246; PotencialDeEutrofizacaoFraccaoDeNutrientesQueAtingemOCompartimentoFinalDeAguaDoce: 0.000189; PotencialDeEutrofizacaoFraccaoDeNutrientesQueAtingemOCompartimentoFinalMarinho: 0.0122; EnergiaRecuperada: 0.00739; ConsumoDeAguaDoce: 0.113; UtilizacaoLiquidaDeAguaDoce: 0.113; ResiduosPerigososEliminados: 0.00221; ResiduosNaoPerigososEliminados: 1.83; MassaTotalDeResiduosRadioactivosEliminados: 0.000394; EnergiaElectricaExportada: 1.55; MateriaisParaRecuperacaoDeEnergia: 0.00739; MateriaisParaReciclagem: 0.0253; UnidadeEPD: 1 m²
Classification: C3010 (Uniformat)
Pset_ProvisionForVoid - Shape: Undefined; Width: 1000 mm; Depth: 1000 mm
IFC.REVIGRÉS-Dados do fabricante-Wall Sweeps - Type: Wall Sweep: REVIGRÉS-LOCUS-RB-9,5X30-SILK-SMOG
IFC.REVIGRÉS-Dados de desempenho-Wall Sweeps - Type: Wall Sweep: REVIGRÉS-LOCUS-RB-9,5X30-SILK-SMOG
IFC.REVIGRÉS-Dados de especificação-Wall Sweeps - Type: Wall Sweep: REVIGRÉS-LOCUS-RB-9,5X30-SILK-SMOG
IFC.REVIGRÉS-Dados geométricos-Wall Sweeps - Type: Wall Sweep: REVIGRÉS-LOCUS-RB-9,5X30-SILK-SMOG
IFC.REVIGRÉS-Dados de sustentabilidade-Wall Sweeps - Type: Wall Sweep: REVIGRÉS-LOCUS-RB-9,5X30-SILK-SMOG

# IfcBuildingElementProxy: Wall Sweep:REVIGRÉS-LOCUS-RB-9,5X30-SOFT GRIP-ALLOY, Wall Sweep:REVIGRÉS-LOCUS-RB-9,5X30-SOFT GRIP-ALLOY:174175
In: Level 1
Type - Pset_ManufacturerTypeInformation - Manufacturer: REVIGRÉS
Type - Pset_ProductRequirements - Category: Wall Sweeps
Type - IFC.REVIGRÉS-Dados gerais-Wall Sweeps - Nome: REVIGRÉS-LOCUS-RB-9.5x30-SOFT GRIP -ALLOY; TipoProduto: Prensado a seco: grupo BIa UGL | Grés porcelânico técnico; NumeroDeRegistoDAP: EPD-REV-20240006-CCC1-EN; ReferenciaDAP: -; UrlDOP: -
Type - IFC.REVIGRÉS-Dados do fabricante-Wall Sweeps - FabricanteURL: https://www.revigres.pt/; ReferenciaModelo: Locus; Acabamento: SOFT; IdentificadorDoOperadorEconomico: 501840856; UrlFabricanteArtigo: https://www.revigres.pt/colecoes/locus; PaisOrigem: Portugal
Type - IFC.REVIGRÉS-Dados de desempenho-Wall Sweeps - Rectilinearidade: ± 0.2% máx ± 1.0 mm; Ortogonalidade: ± 0.2% máx.± 1.5 mm; PlanaridadeDaSuperficie: ± 0.3% máx. ± 1.8 mm; AbsorcaoDeAgua: < 0.05%; ModuloDeRuptura: > 45 N/mm²; ResistenciaAFlexao: > 2000 N; ResistenciaAAbrasaoProfunda: < 120 mm³; DilatacaoTermicaLinear: ≤ 8,0x10-6 °C-1; ResistenciaAoChoqueTermico: Resiste; DurabilidadeInterior: Cumpre; DurabilidadeResistenciaAoGeloDegelo: Resiste; ResistenciaAoEscorregamentoDIN51097: A; ResistenciaAoEscorregamentoENV51097: A; ResistenciaAoDeslizamentoENV12633: Class 2; ResistenciaAoEscorregamentoBS7976: > 36; ResistenciaAoEscorregamentoANSIA1371: ≥0,42; ResistenciaAoDeslizamentoBS7976: > 36; ResistenciaAsManchas: Class 5; LibertacaoDeCadmio: 0; LibertacaoDeChumbo: 0
Type - IFC.REVIGRÉS-Dados de especificação-Wall Sweeps - EPavimento: Sim; ERevestimento: Sim; EExterno: Sim
Type - IFC.REVIGRÉS-Dados geométricos-Wall Sweeps - AlturaNominal: 8.5 mm; ComprimentoNominal: 9.5 mm; LarguraNominal: 29.5 mm
Type - IFC.REVIGRÉS-Dados de sustentabilidade-Wall Sweeps - ItemEParcialmenteReciclado: 0; PotencialPrivacaoDeAguaConsumoDeAguaPonderado: 4.5; EnergiaTermicaExportada: 0; ItemENovo: Sim; ItemEReciclado: Não; VidaÚtilEsperada: 50; SubstanciasPerigosas: Não; PotencialDeEsgotamentoAbioticoDosRecursosFosseis: 203; PotencialDeEsgotamentoAbioticoDosRecursosNaoFosseisMineraisEMetais: 0.000701; PotencialDeAquecimentoGlobalBiogenico: -0.48; CombustiveisFosseisComPotencialDeAquecimentoGlobal: 13.9; PotencialDeAquecimentoGlobalUsoDoSoloEMudancaDeUsoDoSolo: 0.0246; PotencialDeEutrofizacaoFraccaoDeNutrientesQueAtingemOCompartimentoFinalDeAguaDoce: 0.000189; PotencialDeEutrofizacaoFraccaoDeNutrientesQueAtingemOCompartimentoFinalMarinho: 0.0122; EnergiaRecuperada: 0.00739; ConsumoDeAguaDoce: 0.113; UtilizacaoLiquidaDeAguaDoce: 0.113; ResiduosPerigososEliminados: 0.00221; ResiduosNaoPerigososEliminados: 1.83; MassaTotalDeResiduosRadioactivosEliminados: 0.000394; EnergiaElectricaExportada: 1.55; MateriaisParaRecuperacaoDeEnergia: 0.00739; MateriaisParaReciclagem: 0.0253; UnidadeEPD: 1 m²
Classification: C3010 (Uniformat)
Pset_ProvisionForVoid - Shape: Undefined; Width: 1000 mm; Depth: 1000 mm
IFC.REVIGRÉS-Dados do fabricante-Wall Sweeps - Type: Wall Sweep: REVIGRÉS-LOCUS-RB-9,5X30-SOFT GRIP-ALLOY
IFC.REVIGRÉS-Dados de desempenho-Wall Sweeps - Type: Wall Sweep: REVIGRÉS-LOCUS-RB-9,5X30-SOFT GRIP-ALLOY
IFC.REVIGRÉS-Dados de especificação-Wall Sweeps - Type: Wall Sweep: REVIGRÉS-LOCUS-RB-9,5X30-SOFT GRIP-ALLOY
IFC.REVIGRÉS-Dados geométricos-Wall Sweeps - Type: Wall Sweep: REVIGRÉS-LOCUS-RB-9,5X30-SOFT GRIP-ALLOY
IFC.REVIGRÉS-Dados de sustentabilidade-Wall Sweeps - Type: Wall Sweep: REVIGRÉS-LOCUS-RB-9,5X30-SOFT GRIP-ALLOY

# IfcBuildingElementProxy: Wall Sweep:REVIGRÉS-LOCUS-RB-9,5X30-SOFT GRIP-BONE, Wall Sweep:REVIGRÉS-LOCUS-RB-9,5X30-SOFT GRIP-BONE:174602
In: Level 1
Type - Pset_ManufacturerTypeInformation - Manufacturer: REVIGRÉS
Type - Pset_ProductRequirements - Category: Wall Sweeps
Type - IFC.REVIGRÉS-Dados gerais-Wall Sweeps - Nome: REVIGRÉS-LOCUS-RB-9.5x30-SOFT GRIP -BONE; TipoProduto: Prensado a seco: grupo BIa UGL | Grés porcelânico técnico; NumeroDeRegistoDAP: EPD-REV-20240006-CCC1-EN; ReferenciaDAP: -; UrlDOP: -
Type - IFC.REVIGRÉS-Dados do fabricante-Wall Sweeps - FabricanteURL: https://www.revigres.pt/; ReferenciaModelo: Locus; Acabamento: SOFT; IdentificadorDoOperadorEconomico: 501840856; UrlFabricanteArtigo: https://www.revigres.pt/colecoes/locus; PaisOrigem: Portugal
Type - IFC.REVIGRÉS-Dados de desempenho-Wall Sweeps - Rectilinearidade: ± 0.2% máx ± 1.0 mm; Ortogonalidade: ± 0.2% máx.± 1.5 mm; PlanaridadeDaSuperficie: ± 0.3% máx. ± 1.8 mm; AbsorcaoDeAgua: < 0.05%; ModuloDeRuptura: > 45 N/mm²; ResistenciaAFlexao: > 2000 N; ResistenciaAAbrasaoProfunda: < 120 mm³; DilatacaoTermicaLinear: ≤ 8,0x10-6 °C-1; ResistenciaAoChoqueTermico: Resiste; DurabilidadeInterior: Cumpre; DurabilidadeResistenciaAoGeloDegelo: Resiste; ResistenciaAoEscorregamentoDIN51097: A; ResistenciaAoEscorregamentoENV51097: A; ResistenciaAoDeslizamentoENV12633: Class 2; ResistenciaAoEscorregamentoBS7976: > 36; ResistenciaAoEscorregamentoANSIA1371: ≥0,42; ResistenciaAoDeslizamentoBS7976: > 36; ResistenciaAsManchas: Class 5; LibertacaoDeCadmio: 0; LibertacaoDeChumbo: 0
Type - IFC.REVIGRÉS-Dados de especificação-Wall Sweeps - EPavimento: Sim; ERevestimento: Sim; EExterno: Sim
Type - IFC.REVIGRÉS-Dados geométricos-Wall Sweeps - AlturaNominal: 8.5 mm; ComprimentoNominal: 9.5 mm; LarguraNominal: 29.5 mm
Type - IFC.REVIGRÉS-Dados de sustentabilidade-Wall Sweeps - ItemEParcialmenteReciclado: 0; PotencialPrivacaoDeAguaConsumoDeAguaPonderado: 4.5; EnergiaTermicaExportada: 0; ItemENovo: Sim; ItemEReciclado: Não; VidaÚtilEsperada: 50; SubstanciasPerigosas: Não; PotencialDeEsgotamentoAbioticoDosRecursosFosseis: 203; PotencialDeEsgotamentoAbioticoDosRecursosNaoFosseisMineraisEMetais: 0.000701; PotencialDeAquecimentoGlobalBiogenico: -0.48; CombustiveisFosseisComPotencialDeAquecimentoGlobal: 13.9; PotencialDeAquecimentoGlobalUsoDoSoloEMudancaDeUsoDoSolo: 0.0246; PotencialDeEutrofizacaoFraccaoDeNutrientesQueAtingemOCompartimentoFinalDeAguaDoce: 0.000189; PotencialDeEutrofizacaoFraccaoDeNutrientesQueAtingemOCompartimentoFinalMarinho: 0.0122; EnergiaRecuperada: 0.00739; ConsumoDeAguaDoce: 0.113; UtilizacaoLiquidaDeAguaDoce: 0.113; ResiduosPerigososEliminados: 0.00221; ResiduosNaoPerigososEliminados: 1.83; MassaTotalDeResiduosRadioactivosEliminados: 0.000394; EnergiaElectricaExportada: 1.55; MateriaisParaRecuperacaoDeEnergia: 0.00739; MateriaisParaReciclagem: 0.0253; UnidadeEPD: 1 m²
Classification: C3010 (Uniformat)
Pset_ProvisionForVoid - Shape: Undefined; Width: 1000 mm; Depth: 1000 mm
IFC.REVIGRÉS-Dados do fabricante-Wall Sweeps - Type: Wall Sweep: REVIGRÉS-LOCUS-RB-9,5X30-SOFT GRIP-BONE
IFC.REVIGRÉS-Dados de desempenho-Wall Sweeps - Type: Wall Sweep: REVIGRÉS-LOCUS-RB-9,5X30-SOFT GRIP-BONE
IFC.REVIGRÉS-Dados de especificação-Wall Sweeps - Type: Wall Sweep: REVIGRÉS-LOCUS-RB-9,5X30-SOFT GRIP-BONE
IFC.REVIGRÉS-Dados geométricos-Wall Sweeps - Type: Wall Sweep: REVIGRÉS-LOCUS-RB-9,5X30-SOFT GRIP-BONE
IFC.REVIGRÉS-Dados de sustentabilidade-Wall Sweeps - Type: Wall Sweep: REVIGRÉS-LOCUS-RB-9,5X30-SOFT GRIP-BONE

# IfcBuildingElementProxy: Wall Sweep:REVIGRÉS-LOCUS-RB-9,5X30-SOFT GRIP-GRIS, Wall Sweep:REVIGRÉS-LOCUS-RB-9,5X30-SOFT GRIP-GRIS:174844
In: Level 1
Type - Pset_ManufacturerTypeInformation - Manufacturer: REVIGRÉS
Type - Pset_ProductRequirements - Category: Wall Sweeps
Type - IFC.REVIGRÉS-Dados gerais-Wall Sweeps - Nome: REVIGRÉS-LOCUS-RB-9.5x30-SOFT GRIP -GRIS; TipoProduto: Prensado a seco: grupo BIa UGL | Grés porcelânico técnico; NumeroDeRegistoDAP: EPD-REV-20240006-CCC1-EN; ReferenciaDAP: -; UrlDOP: -
Type - IFC.REVIGRÉS-Dados do fabricante-Wall Sweeps - FabricanteURL: https://www.revigres.pt/; ReferenciaModelo: Locus; Acabamento: SOFT; IdentificadorDoOperadorEconomico: 501840856; UrlFabricanteArtigo: https://www.revigres.pt/colecoes/locus; PaisOrigem: Portugal
Type - IFC.REVIGRÉS-Dados de desempenho-Wall Sweeps - Rectilinearidade: ± 0.2% máx ± 1.0 mm; Ortogonalidade: ± 0.2% máx.± 1.5 mm; PlanaridadeDaSuperficie: ± 0.3% máx. ± 1.8 mm; AbsorcaoDeAgua: < 0.05%; ModuloDeRuptura: > 45 N/mm²; ResistenciaAFlexao: > 2000 N; ResistenciaAAbrasaoProfunda: < 120 mm³; DilatacaoTermicaLinear: ≤ 8,0x10-6 °C-1; ResistenciaAoChoqueTermico: Resiste; DurabilidadeInterior: Cumpre; DurabilidadeResistenciaAoGeloDegelo: Resiste; ResistenciaAoEscorregamentoDIN51097: A; ResistenciaAoEscorregamentoENV51097: A; ResistenciaAoDeslizamentoENV12633: Class 2; ResistenciaAoEscorregamentoBS7976: > 36; ResistenciaAoEscorregamentoANSIA1371: ≥0,42; ResistenciaAoDeslizamentoBS7976: > 36; ResistenciaAsManchas: Class 5; LibertacaoDeCadmio: 0; LibertacaoDeChumbo: 0
Type - IFC.REVIGRÉS-Dados de especificação-Wall Sweeps - EPavimento: Sim; ERevestimento: Sim; EExterno: Sim
Type - IFC.REVIGRÉS-Dados geométricos-Wall Sweeps - AlturaNominal: 8.5 mm; ComprimentoNominal: 9.5 mm; LarguraNominal: 29.5 mm
Type - IFC.REVIGRÉS-Dados de sustentabilidade-Wall Sweeps - PotencialPrivacaoDeAguaConsumoDeAguaPonderado: 4.5; EnergiaTermicaExportada: 0; ItemENovo: Sim; ItemEParcialmenteReciclado: 0.23; ItemEReciclado: Sim; VidaÚtilEsperada: 50; SubstanciasPerigosas: Não; PotencialDeEsgotamentoAbioticoDosRecursosFosseis: 203; PotencialDeEsgotamentoAbioticoDosRecursosNaoFosseisMineraisEMetais: 0.000701; PotencialDeAquecimentoGlobalBiogenico: -0.48; CombustiveisFosseisComPotencialDeAquecimentoGlobal: 13.9; PotencialDeAquecimentoGlobalUsoDoSoloEMudancaDeUsoDoSolo: 0.0246; PotencialDeEutrofizacaoFraccaoDeNutrientesQueAtingemOCompartimentoFinalDeAguaDoce: 0.000189; PotencialDeEutrofizacaoFraccaoDeNutrientesQueAtingemOCompartimentoFinalMarinho: 0.0122; EnergiaRecuperada: 0.00739; ConsumoDeAguaDoce: 0.113; UtilizacaoLiquidaDeAguaDoce: 0.113; ResiduosPerigososEliminados: 0.00221; ResiduosNaoPerigososEliminados: 1.83; MassaTotalDeResiduosRadioactivosEliminados: 0.000394; EnergiaElectricaExportada: 1.55; MateriaisParaRecuperacaoDeEnergia: 0.00739; MateriaisParaReciclagem: 0.0253; UnidadeEPD: 1 m²
Classification: C3010 (Uniformat)
Pset_ProvisionForVoid - Shape: Undefined; Width: 1000 mm; Depth: 1000 mm
IFC.REVIGRÉS-Dados do fabricante-Wall Sweeps - Type: Wall Sweep: REVIGRÉS-LOCUS-RB-9,5X30-SOFT GRIP-GRIS
IFC.REVIGRÉS-Dados de desempenho-Wall Sweeps - Type: Wall Sweep: REVIGRÉS-LOCUS-RB-9,5X30-SOFT GRIP-GRIS
IFC.REVIGRÉS-Dados de especificação-Wall Sweeps - Type: Wall Sweep: REVIGRÉS-LOCUS-RB-9,5X30-SOFT GRIP-GRIS
IFC.REVIGRÉS-Dados geométricos-Wall Sweeps - Type: Wall Sweep: REVIGRÉS-LOCUS-RB-9,5X30-SOFT GRIP-GRIS
IFC.REVIGRÉS-Dados de sustentabilidade-Wall Sweeps - Type: Wall Sweep: REVIGRÉS-LOCUS-RB-9,5X30-SOFT GRIP-GRIS

# IfcBuildingElementProxy: Wall Sweep:REVIGRÉS-LOCUS-RB-9,5X30-SOFT GRIP-SMOG, Wall Sweep:REVIGRÉS-LOCUS-RB-9,5X30-SOFT GRIP-SMOG:174868
In: Level 1
Type - Pset_ManufacturerTypeInformation - Manufacturer: REVIGRÉS
Type - Pset_ProductRequirements - Category: Wall Sweeps
Type - IFC.REVIGRÉS-Dados gerais-Wall Sweeps - Nome: REVIGRÉS-LOCUS-RB-9.5x30-SOFT GRIP -SMOG; TipoProduto: Prensado a seco: grupo BIa UGL | Grés porcelânico técnico; NumeroDeRegistoDAP: EPD-REV-20240006-CCC1-EN; ReferenciaDAP: -; UrlDOP: -
Type - IFC.REVIGRÉS-Dados do fabricante-Wall Sweeps - FabricanteURL: https://www.revigres.pt/; ReferenciaModelo: Locus; Acabamento: SOFT; IdentificadorDoOperadorEconomico: 501840856; UrlFabricanteArtigo: https://www.revigres.pt/colecoes/locus; PaisOrigem: Portugal
Type - IFC.REVIGRÉS-Dados de desempenho-Wall Sweeps - Rectilinearidade: ± 0.2% máx ± 1.0 mm; Ortogonalidade: ± 0.2% máx.± 1.5 mm; PlanaridadeDaSuperficie: ± 0.3% máx. ± 1.8 mm; AbsorcaoDeAgua: < 0.05%; ModuloDeRuptura: > 45 N/mm²; ResistenciaAFlexao: > 2000 N; ResistenciaAAbrasaoProfunda: < 120 mm³; DilatacaoTermicaLinear: ≤ 8,0x10-6 °C-1; ResistenciaAoChoqueTermico: Resiste; DurabilidadeInterior: Cumpre; DurabilidadeResistenciaAoGeloDegelo: Resiste; ResistenciaAoEscorregamentoDIN51097: A; ResistenciaAoEscorregamentoENV51097: A; ResistenciaAoDeslizamentoENV12633: Class 2; ResistenciaAoEscorregamentoBS7976: > 36; ResistenciaAoEscorregamentoANSIA1371: ≥0,42; ResistenciaAoDeslizamentoBS7976: > 36; ResistenciaAsManchas: Class 5; LibertacaoDeCadmio: 0; LibertacaoDeChumbo: 0
Type - IFC.REVIGRÉS-Dados de especificação-Wall Sweeps - EPavimento: Sim; ERevestimento: Sim; EExterno: Sim
Type - IFC.REVIGRÉS-Dados geométricos-Wall Sweeps - AlturaNominal: 8.5 mm; ComprimentoNominal: 9.5 mm; LarguraNominal: 29.5 mm
Type - IFC.REVIGRÉS-Dados de sustentabilidade-Wall Sweeps - PotencialPrivacaoDeAguaConsumoDeAguaPonderado: 4.5; EnergiaTermicaExportada: 0; ItemENovo: Sim; ItemEParcialmenteReciclado: 0.29; ItemEReciclado: Sim; VidaÚtilEsperada: 50; SubstanciasPerigosas: Não; PotencialDeEsgotamentoAbioticoDosRecursosFosseis: 203; PotencialDeEsgotamentoAbioticoDosRecursosNaoFosseisMineraisEMetais: 0.000701; PotencialDeAquecimentoGlobalBiogenico: -0.48; CombustiveisFosseisComPotencialDeAquecimentoGlobal: 13.9; PotencialDeAquecimentoGlobalUsoDoSoloEMudancaDeUsoDoSolo: 0.0246; PotencialDeEutrofizacaoFraccaoDeNutrientesQueAtingemOCompartimentoFinalDeAguaDoce: 0.000189; PotencialDeEutrofizacaoFraccaoDeNutrientesQueAtingemOCompartimentoFinalMarinho: 0.0122; EnergiaRecuperada: 0.00739; ConsumoDeAguaDoce: 0.113; UtilizacaoLiquidaDeAguaDoce: 0.113; ResiduosPerigososEliminados: 0.00221; ResiduosNaoPerigososEliminados: 1.83; MassaTotalDeResiduosRadioactivosEliminados: 0.000394; EnergiaElectricaExportada: 1.55; MateriaisParaRecuperacaoDeEnergia: 0.00739; MateriaisParaReciclagem: 0.0253; UnidadeEPD: 1 m²
Classification: C3010 (Uniformat)
Pset_ProvisionForVoid - Shape: Undefined; Width: 1000 mm; Depth: 1000 mm
IFC.REVIGRÉS-Dados do fabricante-Wall Sweeps - Type: Wall Sweep: REVIGRÉS-LOCUS-RB-9,5X30-SOFT GRIP-SMOG
IFC.REVIGRÉS-Dados de desempenho-Wall Sweeps - Type: Wall Sweep: REVIGRÉS-LOCUS-RB-9,5X30-SOFT GRIP-SMOG
IFC.REVIGRÉS-Dados de especificação-Wall Sweeps - Type: Wall Sweep: REVIGRÉS-LOCUS-RB-9,5X30-SOFT GRIP-SMOG
IFC.REVIGRÉS-Dados geométricos-Wall Sweeps - Type: Wall Sweep: REVIGRÉS-LOCUS-RB-9,5X30-SOFT GRIP-SMOG
IFC.REVIGRÉS-Dados de sustentabilidade-Wall Sweeps - Type: Wall Sweep: REVIGRÉS-LOCUS-RB-9,5X30-SOFT GRIP-SMOG

# IfcWallStandardCase: Basic Wall:Wall 1 (8)
In: Level 1
Type - PredefinedType: STANDARD
Type - Pset_ElementShading - Roughness: 304.8 mm
Type - Pset_ProductRequirements - Category: Walls
Type - Pset_QuantityTakeOff - Reference: Wall 1
Type - Pset_ReinforcementBarPitchOfWall - Reference: Wall 1
Type - Pset_WallCommon - Reference: Wall 1; IsExternal: no
Pset_QuantityTakeOff - sets with these values: 2
Pset_WallCommon - IsExternal: yes; ExtendToStructure: no; LoadBearing: no
Name (Basic Wall:Wall 1:...)
104322
158840
158991
159220
159471
159483
159823
160038
